VERSION 5.7 ;
  NOWIREEXTENSIONATPIN ON ;
  DIVIDERCHAR "/" ;
  BUSBITCHARS "[]" ;
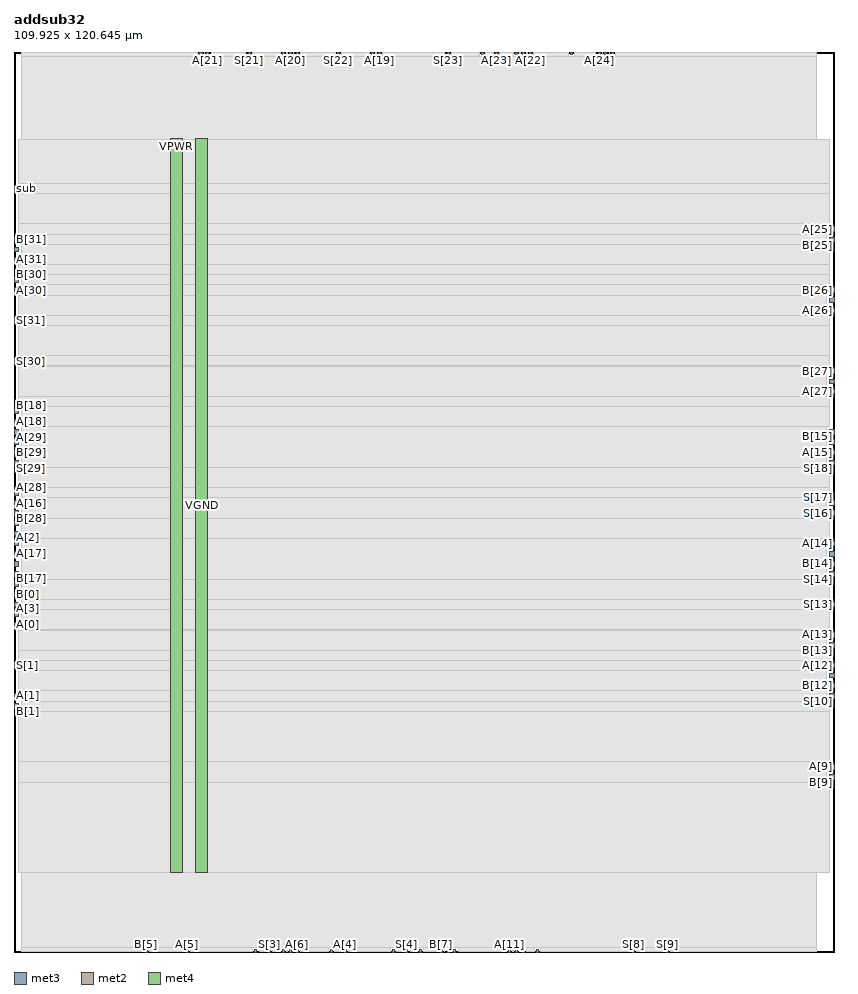
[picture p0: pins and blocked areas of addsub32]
MACRO addsub32
  CLASS BLOCK ;
  FOREIGN addsub32 ;
  ORIGIN 0.000 0.000 ;
  SIZE 109.925 BY 120.645 ;
  PIN A[0]
    DIRECTION INPUT ;
    USE SIGNAL ;
    ANTENNAGATEAREA 0.213000 ;
    PORT
      LAYER met3 ;
        RECT 0.000 43.560 0.600 44.160 ;
    END
  END A[0]
  PIN A[10]
    DIRECTION INPUT ;
    USE SIGNAL ;
    ANTENNAGATEAREA 0.213000 ;
    PORT
      LAYER met2 ;
        RECT 58.050 0.000 58.330 0.280 ;
    END
  END A[10]
  PIN A[11]
    DIRECTION INPUT ;
    USE SIGNAL ;
    ANTENNAGATEAREA 0.213000 ;
    PORT
      LAYER met2 ;
        RECT 66.330 0.000 66.610 0.280 ;
    END
  END A[11]
  PIN A[12]
    DIRECTION INPUT ;
    USE SIGNAL ;
    ANTENNAGATEAREA 0.213000 ;
    PORT
      LAYER met3 ;
        RECT 109.325 38.120 109.925 38.720 ;
    END
  END A[12]
  PIN A[13]
    DIRECTION INPUT ;
    USE SIGNAL ;
    ANTENNAGATEAREA 0.213000 ;
    PORT
      LAYER met3 ;
        RECT 109.325 42.200 109.925 42.800 ;
    END
  END A[13]
  PIN A[14]
    DIRECTION INPUT ;
    USE SIGNAL ;
    ANTENNAGATEAREA 0.213000 ;
    PORT
      LAYER met3 ;
        RECT 109.325 54.440 109.925 55.040 ;
    END
  END A[14]
  PIN A[15]
    DIRECTION INPUT ;
    USE SIGNAL ;
    ANTENNAGATEAREA 0.213000 ;
    PORT
      LAYER met3 ;
        RECT 109.325 66.680 109.925 67.280 ;
    END
  END A[15]
  PIN A[16]
    DIRECTION INPUT ;
    USE SIGNAL ;
    ANTENNAGATEAREA 0.213000 ;
    PORT
      LAYER met3 ;
        RECT 0.000 59.880 0.600 60.480 ;
    END
  END A[16]
  PIN A[17]
    DIRECTION INPUT ;
    USE SIGNAL ;
    ANTENNAGATEAREA 0.213000 ;
    PORT
      LAYER met3 ;
        RECT 0.000 53.080 0.600 53.680 ;
    END
  END A[17]
  PIN A[18]
    DIRECTION INPUT ;
    USE SIGNAL ;
    ANTENNAGATEAREA 0.213000 ;
    PORT
      LAYER met3 ;
        RECT 0.000 70.760 0.600 71.360 ;
    END
  END A[18]
  PIN A[19]
    DIRECTION INPUT ;
    USE SIGNAL ;
    ANTENNAGATEAREA 0.213000 ;
    PORT
      LAYER met2 ;
        RECT 48.850 120.365 49.130 120.645 ;
    END
  END A[19]
  PIN A[1]
    DIRECTION INPUT ;
    USE SIGNAL ;
    ANTENNAGATEAREA 0.213000 ;
    PORT
      LAYER met3 ;
        RECT 0.000 34.040 0.600 34.640 ;
    END
  END A[1]
  PIN A[20]
    DIRECTION INPUT ;
    USE SIGNAL ;
    ANTENNAGATEAREA 0.213000 ;
    PORT
      LAYER met2 ;
        RECT 36.890 120.365 37.170 120.645 ;
    END
  END A[20]
  PIN A[21]
    DIRECTION INPUT ;
    USE SIGNAL ;
    ANTENNAGATEAREA 0.213000 ;
    PORT
      LAYER met2 ;
        RECT 25.850 120.365 26.130 120.645 ;
    END
  END A[21]
  PIN A[22]
    DIRECTION INPUT ;
    USE SIGNAL ;
    ANTENNAGATEAREA 0.213000 ;
    PORT
      LAYER met2 ;
        RECT 69.090 120.365 69.370 120.645 ;
    END
  END A[22]
  PIN A[23]
    DIRECTION INPUT ;
    USE SIGNAL ;
    ANTENNAGATEAREA 0.213000 ;
    PORT
      LAYER met2 ;
        RECT 64.490 120.365 64.770 120.645 ;
    END
  END A[23]
  PIN A[24]
    DIRECTION INPUT ;
    USE SIGNAL ;
    ANTENNAGATEAREA 0.213000 ;
    PORT
      LAYER met2 ;
        RECT 78.290 120.365 78.570 120.645 ;
    END
  END A[24]
  PIN A[25]
    DIRECTION INPUT ;
    USE SIGNAL ;
    ANTENNAGATEAREA 0.213000 ;
    PORT
      LAYER met3 ;
        RECT 109.325 96.600 109.925 97.200 ;
    END
  END A[25]
  PIN A[26]
    DIRECTION INPUT ;
    USE SIGNAL ;
    ANTENNAGATEAREA 0.213000 ;
    PORT
      LAYER met3 ;
        RECT 109.325 85.720 109.925 86.320 ;
    END
  END A[26]
  PIN A[27]
    DIRECTION INPUT ;
    USE SIGNAL ;
    ANTENNAGATEAREA 0.213000 ;
    PORT
      LAYER met3 ;
        RECT 109.325 74.840 109.925 75.440 ;
    END
  END A[27]
  PIN A[28]
    DIRECTION INPUT ;
    USE SIGNAL ;
    ANTENNAGATEAREA 0.213000 ;
    PORT
      LAYER met3 ;
        RECT 0.000 61.240 0.600 61.840 ;
    END
  END A[28]
  PIN A[29]
    DIRECTION INPUT ;
    USE SIGNAL ;
    ANTENNAGATEAREA 0.213000 ;
    PORT
      LAYER met3 ;
        RECT 0.000 69.400 0.600 70.000 ;
    END
  END A[29]
  PIN A[2]
    DIRECTION INPUT ;
    USE SIGNAL ;
    ANTENNAGATEAREA 0.213000 ;
    PORT
      LAYER met3 ;
        RECT 0.000 54.440 0.600 55.040 ;
    END
  END A[2]
  PIN A[30]
    DIRECTION INPUT ;
    USE SIGNAL ;
    ANTENNAGATEAREA 0.213000 ;
    PORT
      LAYER met3 ;
        RECT 0.000 88.440 0.600 89.040 ;
    END
  END A[30]
  PIN A[31]
    DIRECTION INPUT ;
    USE SIGNAL ;
    ANTENNAGATEAREA 0.213000 ;
    PORT
      LAYER met3 ;
        RECT 0.000 92.520 0.600 93.120 ;
    END
  END A[31]
  PIN A[3]
    DIRECTION INPUT ;
    USE SIGNAL ;
    ANTENNAGATEAREA 0.213000 ;
    PORT
      LAYER met3 ;
        RECT 0.000 44.920 0.600 45.520 ;
    END
  END A[3]
  PIN A[4]
    DIRECTION INPUT ;
    USE SIGNAL ;
    ANTENNAGATEAREA 0.213000 ;
    PORT
      LAYER met2 ;
        RECT 44.250 0.000 44.530 0.280 ;
    END
  END A[4]
  PIN A[5]
    DIRECTION INPUT ;
    USE SIGNAL ;
    ANTENNAGATEAREA 0.213000 ;
    PORT
      LAYER met2 ;
        RECT 23.090 0.000 23.370 0.280 ;
    END
  END A[5]
  PIN A[6]
    DIRECTION INPUT ;
    USE SIGNAL ;
    ANTENNAGATEAREA 0.213000 ;
    PORT
      LAYER met2 ;
        RECT 37.810 0.000 38.090 0.280 ;
    END
  END A[6]
  PIN A[7]
    DIRECTION INPUT ;
    USE SIGNAL ;
    ANTENNAGATEAREA 0.213000 ;
    PORT
      LAYER met2 ;
        RECT 54.370 0.000 54.650 0.280 ;
    END
  END A[7]
  PIN A[8]
    DIRECTION INPUT ;
    USE SIGNAL ;
    ANTENNAGATEAREA 0.213000 ;
    PORT
      LAYER met2 ;
        RECT 70.010 0.000 70.290 0.280 ;
    END
  END A[8]
  PIN A[9]
    DIRECTION INPUT ;
    USE SIGNAL ;
    ANTENNAGATEAREA 0.213000 ;
    PORT
      LAYER met3 ;
        RECT 109.325 24.520 109.925 25.120 ;
    END
  END A[9]
  PIN B[0]
    DIRECTION INPUT ;
    USE SIGNAL ;
    ANTENNAGATEAREA 0.126000 ;
    PORT
      LAYER met3 ;
        RECT 0.000 47.640 0.600 48.240 ;
    END
  END B[0]
  PIN B[10]
    DIRECTION INPUT ;
    USE SIGNAL ;
    ANTENNAGATEAREA 0.213000 ;
    PORT
      LAYER met2 ;
        RECT 58.970 0.000 59.250 0.280 ;
    END
  END B[10]
  PIN B[11]
    DIRECTION INPUT ;
    USE SIGNAL ;
    ANTENNAGATEAREA 0.213000 ;
    PORT
      LAYER met2 ;
        RECT 67.250 0.000 67.530 0.280 ;
    END
  END B[11]
  PIN B[12]
    DIRECTION INPUT ;
    USE SIGNAL ;
    ANTENNAGATEAREA 0.213000 ;
    PORT
      LAYER met3 ;
        RECT 109.325 35.400 109.925 36.000 ;
    END
  END B[12]
  PIN B[13]
    DIRECTION INPUT ;
    USE SIGNAL ;
    ANTENNAGATEAREA 0.213000 ;
    PORT
      LAYER met3 ;
        RECT 109.325 40.840 109.925 41.440 ;
    END
  END B[13]
  PIN B[14]
    DIRECTION INPUT ;
    USE SIGNAL ;
    ANTENNAGATEAREA 0.213000 ;
    PORT
      LAYER met3 ;
        RECT 109.325 51.720 109.925 52.320 ;
    END
  END B[14]
  PIN B[15]
    DIRECTION INPUT ;
    USE SIGNAL ;
    ANTENNAGATEAREA 0.213000 ;
    PORT
      LAYER met3 ;
        RECT 109.325 68.040 109.925 68.640 ;
    END
  END B[15]
  PIN B[16]
    DIRECTION INPUT ;
    USE SIGNAL ;
    ANTENNAGATEAREA 0.213000 ;
    PORT
      LAYER met3 ;
        RECT 0.000 57.160 0.600 57.760 ;
    END
  END B[16]
  PIN B[17]
    DIRECTION INPUT ;
    USE SIGNAL ;
    ANTENNAGATEAREA 0.213000 ;
    PORT
      LAYER met3 ;
        RECT 0.000 49.000 0.600 49.600 ;
    END
  END B[17]
  PIN B[18]
    DIRECTION INPUT ;
    USE SIGNAL ;
    ANTENNAGATEAREA 0.213000 ;
    PORT
      LAYER met3 ;
        RECT 0.000 72.120 0.600 72.720 ;
    END
  END B[18]
  PIN B[19]
    DIRECTION INPUT ;
    USE SIGNAL ;
    ANTENNAGATEAREA 0.213000 ;
    PORT
      LAYER met2 ;
        RECT 47.930 120.365 48.210 120.645 ;
    END
  END B[19]
  PIN B[1]
    DIRECTION INPUT ;
    USE SIGNAL ;
    ANTENNAGATEAREA 0.213000 ;
    PORT
      LAYER met3 ;
        RECT 0.000 32.680 0.600 33.280 ;
    END
  END B[1]
  PIN B[20]
    DIRECTION INPUT ;
    USE SIGNAL ;
    ANTENNAGATEAREA 0.213000 ;
    PORT
      LAYER met2 ;
        RECT 35.970 120.365 36.250 120.645 ;
    END
  END B[20]
  PIN B[21]
    DIRECTION INPUT ;
    USE SIGNAL ;
    ANTENNAGATEAREA 0.213000 ;
    PORT
      LAYER met2 ;
        RECT 24.930 120.365 25.210 120.645 ;
    END
  END B[21]
  PIN B[22]
    DIRECTION INPUT ;
    USE SIGNAL ;
    ANTENNAGATEAREA 0.213000 ;
    PORT
      LAYER met2 ;
        RECT 68.170 120.365 68.450 120.645 ;
    END
  END B[22]
  PIN B[23]
    DIRECTION INPUT ;
    USE SIGNAL ;
    ANTENNAGATEAREA 0.213000 ;
    PORT
      LAYER met2 ;
        RECT 67.250 120.365 67.530 120.645 ;
    END
  END B[23]
  PIN B[24]
    DIRECTION INPUT ;
    USE SIGNAL ;
    ANTENNAGATEAREA 0.213000 ;
    PORT
      LAYER met2 ;
        RECT 79.210 120.365 79.490 120.645 ;
    END
  END B[24]
  PIN B[25]
    DIRECTION INPUT ;
    USE SIGNAL ;
    ANTENNAGATEAREA 0.213000 ;
    PORT
      LAYER met3 ;
        RECT 109.325 95.240 109.925 95.840 ;
    END
  END B[25]
  PIN B[26]
    DIRECTION INPUT ;
    USE SIGNAL ;
    ANTENNAGATEAREA 0.213000 ;
    PORT
      LAYER met3 ;
        RECT 109.325 88.440 109.925 89.040 ;
    END
  END B[26]
  PIN B[27]
    DIRECTION INPUT ;
    USE SIGNAL ;
    ANTENNAGATEAREA 0.213000 ;
    PORT
      LAYER met3 ;
        RECT 109.325 77.560 109.925 78.160 ;
    END
  END B[27]
  PIN B[28]
    DIRECTION INPUT ;
    USE SIGNAL ;
    ANTENNAGATEAREA 0.213000 ;
    PORT
      LAYER met3 ;
        RECT 0.000 58.520 0.600 59.120 ;
    END
  END B[28]
  PIN B[29]
    DIRECTION INPUT ;
    USE SIGNAL ;
    ANTENNAGATEAREA 0.213000 ;
    PORT
      LAYER met3 ;
        RECT 0.000 66.680 0.600 67.280 ;
    END
  END B[29]
  PIN B[2]
    DIRECTION INPUT ;
    USE SIGNAL ;
    ANTENNAGATEAREA 0.213000 ;
    PORT
      LAYER met3 ;
        RECT 0.000 55.800 0.600 56.400 ;
    END
  END B[2]
  PIN B[30]
    DIRECTION INPUT ;
    USE SIGNAL ;
    ANTENNAGATEAREA 0.213000 ;
    PORT
      LAYER met3 ;
        RECT 0.000 89.800 0.600 90.400 ;
    END
  END B[30]
  PIN B[31]
    DIRECTION INPUT ;
    USE SIGNAL ;
    ANTENNAGATEAREA 0.213000 ;
    PORT
      LAYER met3 ;
        RECT 0.000 95.240 0.600 95.840 ;
    END
  END B[31]
  PIN B[3]
    DIRECTION INPUT ;
    USE SIGNAL ;
    ANTENNAGATEAREA 0.213000 ;
    PORT
      LAYER met3 ;
        RECT 0.000 46.280 0.600 46.880 ;
    END
  END B[3]
  PIN B[4]
    DIRECTION INPUT ;
    USE SIGNAL ;
    ANTENNAGATEAREA 0.213000 ;
    PORT
      LAYER met2 ;
        RECT 42.410 0.000 42.690 0.280 ;
    END
  END B[4]
  PIN B[5]
    DIRECTION INPUT ;
    USE SIGNAL ;
    ANTENNAGATEAREA 0.213000 ;
    PORT
      LAYER met2 ;
        RECT 17.570 0.000 17.850 0.280 ;
    END
  END B[5]
  PIN B[6]
    DIRECTION INPUT ;
    USE SIGNAL ;
    ANTENNAGATEAREA 0.213000 ;
    PORT
      LAYER met2 ;
        RECT 36.890 0.000 37.170 0.280 ;
    END
  END B[6]
  PIN B[7]
    DIRECTION INPUT ;
    USE SIGNAL ;
    ANTENNAGATEAREA 0.213000 ;
    PORT
      LAYER met2 ;
        RECT 57.130 0.000 57.410 0.280 ;
    END
  END B[7]
  PIN B[8]
    DIRECTION INPUT ;
    USE SIGNAL ;
    ANTENNAGATEAREA 0.213000 ;
    PORT
      LAYER met2 ;
        RECT 68.170 0.000 68.450 0.280 ;
    END
  END B[8]
  PIN B[9]
    DIRECTION INPUT ;
    USE SIGNAL ;
    ANTENNAGATEAREA 0.213000 ;
    PORT
      LAYER met3 ;
        RECT 109.325 23.160 109.925 23.760 ;
    END
  END B[9]
  PIN S[0]
    DIRECTION OUTPUT ;
    USE SIGNAL ;
    ANTENNADIFFAREA 0.702900 ;
    PORT
      LAYER met3 ;
        RECT 0.000 50.360 0.600 50.960 ;
    END
  END S[0]
  PIN S[10]
    DIRECTION OUTPUT ;
    USE SIGNAL ;
    ANTENNADIFFAREA 1.336500 ;
    PORT
      LAYER met3 ;
        RECT 109.325 34.040 109.925 34.640 ;
    END
  END S[10]
  PIN S[11]
    DIRECTION OUTPUT ;
    USE SIGNAL ;
    ANTENNADIFFAREA 1.336500 ;
    PORT
      LAYER met3 ;
        RECT 109.325 36.760 109.925 37.360 ;
    END
  END S[11]
  PIN S[12]
    DIRECTION OUTPUT ;
    USE SIGNAL ;
    ANTENNADIFFAREA 1.336500 ;
    PORT
      LAYER met3 ;
        RECT 109.325 53.080 109.925 53.680 ;
    END
  END S[12]
  PIN S[13]
    DIRECTION OUTPUT ;
    USE SIGNAL ;
    ANTENNADIFFAREA 1.336500 ;
    PORT
      LAYER met3 ;
        RECT 109.325 46.280 109.925 46.880 ;
    END
  END S[13]
  PIN S[14]
    DIRECTION OUTPUT ;
    USE SIGNAL ;
    ANTENNADIFFAREA 1.336500 ;
    PORT
      LAYER met3 ;
        RECT 109.325 50.360 109.925 50.960 ;
    END
  END S[14]
  PIN S[15]
    DIRECTION OUTPUT ;
    USE SIGNAL ;
    ANTENNADIFFAREA 0.891000 ;
    PORT
      LAYER met3 ;
        RECT 109.325 69.400 109.925 70.000 ;
    END
  END S[15]
  PIN S[16]
    DIRECTION OUTPUT ;
    USE SIGNAL ;
    ANTENNADIFFAREA 1.336500 ;
    PORT
      LAYER met3 ;
        RECT 109.325 58.520 109.925 59.120 ;
    END
  END S[16]
  PIN S[17]
    DIRECTION OUTPUT ;
    USE SIGNAL ;
    ANTENNADIFFAREA 1.336500 ;
    PORT
      LAYER met3 ;
        RECT 109.325 59.880 109.925 60.480 ;
    END
  END S[17]
  PIN S[18]
    DIRECTION OUTPUT ;
    USE SIGNAL ;
    ANTENNADIFFAREA 0.445500 ;
    PORT
      LAYER met3 ;
        RECT 109.325 65.320 109.925 65.920 ;
    END
  END S[18]
  PIN S[19]
    DIRECTION OUTPUT ;
    USE SIGNAL ;
    ANTENNADIFFAREA 0.795200 ;
    PORT
      LAYER met2 ;
        RECT 62.650 120.365 62.930 120.645 ;
    END
  END S[19]
  PIN S[1]
    DIRECTION OUTPUT ;
    USE SIGNAL ;
    ANTENNADIFFAREA 1.336500 ;
    PORT
      LAYER met3 ;
        RECT 0.000 38.120 0.600 38.720 ;
    END
  END S[1]
  PIN S[20]
    DIRECTION OUTPUT ;
    USE SIGNAL ;
    ANTENNADIFFAREA 1.336500 ;
    PORT
      LAYER met2 ;
        RECT 37.810 120.365 38.090 120.645 ;
    END
  END S[20]
  PIN S[21]
    DIRECTION OUTPUT ;
    USE SIGNAL ;
    ANTENNADIFFAREA 1.782000 ;
    PORT
      LAYER met2 ;
        RECT 31.370 120.365 31.650 120.645 ;
    END
  END S[21]
  PIN S[22]
    DIRECTION OUTPUT ;
    USE SIGNAL ;
    ANTENNADIFFAREA 1.782000 ;
    PORT
      LAYER met2 ;
        RECT 43.330 120.365 43.610 120.645 ;
    END
  END S[22]
  PIN S[23]
    DIRECTION OUTPUT ;
    USE SIGNAL ;
    ANTENNADIFFAREA 1.336500 ;
    PORT
      LAYER met2 ;
        RECT 58.050 120.365 58.330 120.645 ;
    END
  END S[23]
  PIN S[24]
    DIRECTION OUTPUT ;
    USE SIGNAL ;
    ANTENNADIFFAREA 0.383400 ;
    PORT
      LAYER met2 ;
        RECT 74.610 120.365 74.890 120.645 ;
    END
  END S[24]
  PIN S[25]
    DIRECTION OUTPUT ;
    USE SIGNAL ;
    ANTENNADIFFAREA 0.383400 ;
    PORT
      LAYER met2 ;
        RECT 80.130 120.365 80.410 120.645 ;
    END
  END S[25]
  PIN S[26]
    DIRECTION OUTPUT ;
    USE SIGNAL ;
    ANTENNADIFFAREA 0.383400 ;
    PORT
      LAYER met3 ;
        RECT 109.325 87.080 109.925 87.680 ;
    END
  END S[26]
  PIN S[27]
    DIRECTION OUTPUT ;
    USE SIGNAL ;
    ANTENNADIFFAREA 0.795200 ;
    PORT
      LAYER met3 ;
        RECT 109.325 76.200 109.925 76.800 ;
    END
  END S[27]
  PIN S[28]
    DIRECTION OUTPUT ;
    USE SIGNAL ;
    ANTENNADIFFAREA 1.336500 ;
    PORT
      LAYER met3 ;
        RECT 0.000 68.040 0.600 68.640 ;
    END
  END S[28]
  PIN S[29]
    DIRECTION OUTPUT ;
    USE SIGNAL ;
    ANTENNADIFFAREA 1.336500 ;
    PORT
      LAYER met3 ;
        RECT 0.000 65.320 0.600 65.920 ;
    END
  END S[29]
  PIN S[2]
    DIRECTION OUTPUT ;
    USE SIGNAL ;
    ANTENNADIFFAREA 0.795200 ;
    PORT
      LAYER met3 ;
        RECT 0.000 51.720 0.600 52.320 ;
    END
  END S[2]
  PIN S[30]
    DIRECTION OUTPUT ;
    USE SIGNAL ;
    ANTENNADIFFAREA 1.336500 ;
    PORT
      LAYER met3 ;
        RECT 0.000 78.920 0.600 79.520 ;
    END
  END S[30]
  PIN S[31]
    DIRECTION OUTPUT ;
    USE SIGNAL ;
    ANTENNADIFFAREA 1.336500 ;
    PORT
      LAYER met3 ;
        RECT 0.000 84.360 0.600 84.960 ;
    END
  END S[31]
  PIN S[3]
    DIRECTION OUTPUT ;
    USE SIGNAL ;
    ANTENNADIFFAREA 1.336500 ;
    PORT
      LAYER met2 ;
        RECT 34.130 0.000 34.410 0.280 ;
    END
  END S[3]
  PIN S[4]
    DIRECTION OUTPUT ;
    USE SIGNAL ;
    ANTENNADIFFAREA 1.336500 ;
    PORT
      LAYER met2 ;
        RECT 52.530 0.000 52.810 0.280 ;
    END
  END S[4]
  PIN S[5]
    DIRECTION OUTPUT ;
    USE SIGNAL ;
    ANTENNADIFFAREA 0.795200 ;
    PORT
      LAYER met2 ;
        RECT 35.970 0.000 36.250 0.280 ;
    END
  END S[5]
  PIN S[6]
    DIRECTION OUTPUT ;
    USE SIGNAL ;
    ANTENNADIFFAREA 1.336500 ;
    PORT
      LAYER met2 ;
        RECT 32.290 0.000 32.570 0.280 ;
    END
  END S[6]
  PIN S[7]
    DIRECTION OUTPUT ;
    USE SIGNAL ;
    ANTENNADIFFAREA 0.795200 ;
    PORT
      LAYER met2 ;
        RECT 50.690 0.000 50.970 0.280 ;
    END
  END S[7]
  PIN S[8]
    DIRECTION OUTPUT ;
    USE SIGNAL ;
    ANTENNADIFFAREA 1.336500 ;
    PORT
      LAYER met2 ;
        RECT 82.890 0.000 83.170 0.280 ;
    END
  END S[8]
  PIN S[9]
    DIRECTION OUTPUT ;
    USE SIGNAL ;
    ANTENNADIFFAREA 1.336500 ;
    PORT
      LAYER met2 ;
        RECT 87.490 0.000 87.770 0.280 ;
    END
  END S[9]
  PIN VGND
    DIRECTION INOUT ;
    USE GROUND ;
    PORT
      LAYER met4 ;
        RECT 24.340 10.640 25.940 109.040 ;
    END
  END VGND
  PIN VPWR
    DIRECTION INOUT ;
    USE POWER ;
    PORT
      LAYER met4 ;
        RECT 21.040 10.640 22.640 109.040 ;
    END
  END VPWR
  PIN carryOut
    DIRECTION OUTPUT ;
    USE SIGNAL ;
    ANTENNADIFFAREA 1.336500 ;
    PORT
      LAYER met3 ;
        RECT 0.000 93.880 0.600 94.480 ;
    END
  END carryOut
  PIN sub
    DIRECTION INPUT ;
    USE SIGNAL ;
    ANTENNAGATEAREA 0.742500 ;
    PORT
      LAYER met3 ;
        RECT 0.000 102.040 0.600 102.640 ;
    END
  END sub
  OBS
      LAYER nwell ;
        RECT 5.330 10.795 104.150 108.885 ;
      LAYER li1 ;
        RECT 5.520 10.795 103.960 108.885 ;
      LAYER met1 ;
        RECT 0.990 4.120 107.570 109.040 ;
      LAYER met2 ;
        RECT 1.010 120.085 24.650 120.575 ;
        RECT 25.490 120.085 25.570 120.575 ;
        RECT 26.410 120.085 31.090 120.575 ;
        RECT 31.930 120.085 35.690 120.575 ;
        RECT 36.530 120.085 36.610 120.575 ;
        RECT 37.450 120.085 37.530 120.575 ;
        RECT 38.370 120.085 43.050 120.575 ;
        RECT 43.890 120.085 47.650 120.575 ;
        RECT 48.490 120.085 48.570 120.575 ;
        RECT 49.410 120.085 57.770 120.575 ;
        RECT 58.610 120.085 62.370 120.575 ;
        RECT 63.210 120.085 64.210 120.575 ;
        RECT 65.050 120.085 66.970 120.575 ;
        RECT 67.810 120.085 67.890 120.575 ;
        RECT 68.730 120.085 68.810 120.575 ;
        RECT 69.650 120.085 74.330 120.575 ;
        RECT 75.170 120.085 78.010 120.575 ;
        RECT 78.850 120.085 78.930 120.575 ;
        RECT 79.770 120.085 79.850 120.575 ;
        RECT 80.690 120.085 107.550 120.575 ;
        RECT 1.010 0.560 107.550 120.085 ;
        RECT 1.010 0.070 17.290 0.560 ;
        RECT 18.130 0.070 22.810 0.560 ;
        RECT 23.650 0.070 32.010 0.560 ;
        RECT 32.850 0.070 33.850 0.560 ;
        RECT 34.690 0.070 35.690 0.560 ;
        RECT 36.530 0.070 36.610 0.560 ;
        RECT 37.450 0.070 37.530 0.560 ;
        RECT 38.370 0.070 42.130 0.560 ;
        RECT 42.970 0.070 43.970 0.560 ;
        RECT 44.810 0.070 50.410 0.560 ;
        RECT 51.250 0.070 52.250 0.560 ;
        RECT 53.090 0.070 54.090 0.560 ;
        RECT 54.930 0.070 56.850 0.560 ;
        RECT 57.690 0.070 57.770 0.560 ;
        RECT 58.610 0.070 58.690 0.560 ;
        RECT 59.530 0.070 66.050 0.560 ;
        RECT 66.890 0.070 66.970 0.560 ;
        RECT 67.810 0.070 67.890 0.560 ;
        RECT 68.730 0.070 69.730 0.560 ;
        RECT 70.570 0.070 82.610 0.560 ;
        RECT 83.450 0.070 87.210 0.560 ;
        RECT 88.050 0.070 107.550 0.560 ;
      LAYER met3 ;
        RECT 0.600 103.040 109.325 108.965 ;
        RECT 1.000 101.640 109.325 103.040 ;
        RECT 0.600 97.600 109.325 101.640 ;
        RECT 0.600 96.240 108.925 97.600 ;
        RECT 1.000 94.840 108.925 96.240 ;
        RECT 1.000 92.120 109.325 94.840 ;
        RECT 0.600 90.800 109.325 92.120 ;
        RECT 1.000 89.440 109.325 90.800 ;
        RECT 1.000 88.040 108.925 89.440 ;
        RECT 0.600 85.360 108.925 88.040 ;
        RECT 1.000 85.320 108.925 85.360 ;
        RECT 1.000 83.960 109.325 85.320 ;
        RECT 0.600 79.920 109.325 83.960 ;
        RECT 1.000 78.560 109.325 79.920 ;
        RECT 1.000 78.520 108.925 78.560 ;
        RECT 0.600 74.440 108.925 78.520 ;
        RECT 0.600 73.120 109.325 74.440 ;
        RECT 1.000 70.400 109.325 73.120 ;
        RECT 1.000 64.920 108.925 70.400 ;
        RECT 0.600 62.240 109.325 64.920 ;
        RECT 1.000 60.880 109.325 62.240 ;
        RECT 1.000 58.120 108.925 60.880 ;
        RECT 1.000 55.440 109.325 58.120 ;
        RECT 1.000 49.960 108.925 55.440 ;
        RECT 1.000 47.280 109.325 49.960 ;
        RECT 1.000 45.880 108.925 47.280 ;
        RECT 1.000 43.200 109.325 45.880 ;
        RECT 1.000 43.160 108.925 43.200 ;
        RECT 0.600 40.440 108.925 43.160 ;
        RECT 0.600 39.120 109.325 40.440 ;
        RECT 1.000 37.720 108.925 39.120 ;
        RECT 0.600 35.040 108.925 37.720 ;
        RECT 1.000 33.640 108.925 35.040 ;
        RECT 1.000 32.280 109.325 33.640 ;
        RECT 0.600 25.520 109.325 32.280 ;
        RECT 0.600 22.760 108.925 25.520 ;
        RECT 0.600 10.715 109.325 22.760 ;
  END
END addsub32
END LIBRARY

